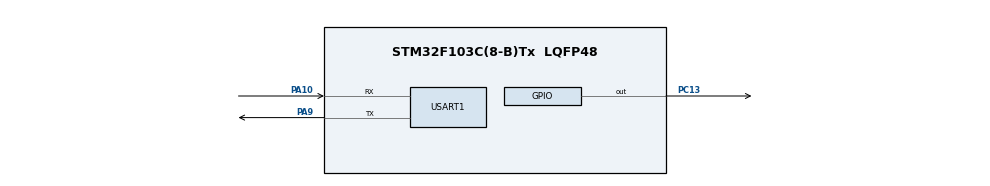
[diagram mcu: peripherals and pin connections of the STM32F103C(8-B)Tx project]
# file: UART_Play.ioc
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Mcu.Family=STM32F1
Mcu.Name=STM32F103C(8-B)Tx
Mcu.Package=LQFP48
NVIC.PriorityGroup=NVIC_PRIORITYGROUP_4
NVIC.USART1_IRQn=true\:0\:0\:false\:false\:true\:true\:true\:true
PA10.Mode=Asynchronous
PA10.Signal=USART1_RX
PA9.Mode=Asynchronous
PA9.Signal=USART1_TX
PC13-TAMPER-RTC.Signal=GPIO_Output
ProjectManager.HeapSize=0x200
ProjectManager.StackSize=0x400
ProjectManager.TargetToolchain=STM32CubeIDE
RCC.APB1Freq_Value=8000000
RCC.APB2Freq_Value=8000000
USART1.VirtualMode=VM_ASYNC
VP_SYS_VS_ND.Mode=No_Debug
board=custom

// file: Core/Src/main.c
/* USER CODE BEGIN Header */
/**
  ******************************************************************************
  * @file           : main.c
  * @brief          : Main program body
  ******************************************************************************
  * @attention
  *
  * Copyright (c) 2025 STMicroelectronics.
  * All rights reserved.
  *
  * This software is licensed under terms that can be found in the LICENSE file
  * in the root directory of this software component.
  * If no LICENSE file comes with this software, it is provided AS-IS.
  *
  ******************************************************************************
  */
/* USER CODE END Header */
#include "main.h"
#include <stdbool.h>

UART_HandleTypeDef huart1;

/* USER CODE BEGIN PV */
#define SIZE_DATA 16

uint8_t tx_data[] = "Got data\n\r";
uint8_t rx_data[SIZE_DATA];
uint8_t command_set[] = "PIN_SET";
uint8_t command_reset[] = "PIN_RESET";
bool is_set;
/* USER CODE END PV */

void SystemClock_Config(void);
static void MX_GPIO_Init(void);
static void MX_USART1_UART_Init(void);

int main(void)
{

  /* MCU Configuration--------------------------------------------------------*/

  /* Reset of all peripherals, Initializes the Flash interface and the Systick. */
  HAL_Init();

  /* Configure the system clock */
  SystemClock_Config();

  /* Initialize all configured peripherals */
  MX_GPIO_Init();
  MX_USART1_UART_Init();
  /* USER CODE BEGIN 2 */
  HAL_UART_Receive_IT(&huart1, rx_data, SIZE_DATA);
  is_set = false;

  /* USER CODE END 2 */

  /* Infinite loop */
  while (1)
  {

    /* USER CODE BEGIN 3 */
	  HAL_GPIO_WritePin(GPIOC, GPIO_PIN_13, is_set ? GPIO_PIN_RESET : GPIO_PIN_SET);
	  HAL_Delay(200);
  }
  /* USER CODE END 3 */
}

void SystemClock_Config(void)
{
  RCC_OscInitTypeDef RCC_OscInitStruct = {0};
  RCC_ClkInitTypeDef RCC_ClkInitStruct = {0};

  /** Initializes the RCC Oscillators according to the specified parameters
  * in the RCC_OscInitTypeDef structure.
  */
  RCC_OscInitStruct.OscillatorType = RCC_OSCILLATORTYPE_HSI;
  RCC_OscInitStruct.HSIState = RCC_HSI_ON;
  RCC_OscInitStruct.HSICalibrationValue = RCC_HSICALIBRATION_DEFAULT;
  RCC_OscInitStruct.PLL.PLLState = RCC_PLL_NONE;
  if (HAL_RCC_OscConfig(&RCC_OscInitStruct) != HAL_OK)
  {
    Error_Handler();
  }

  /** Initializes the CPU, AHB and APB buses clocks
  */
  RCC_ClkInitStruct.ClockType = RCC_CLOCKTYPE_HCLK|RCC_CLOCKTYPE_SYSCLK
                              |RCC_CLOCKTYPE_PCLK1|RCC_CLOCKTYPE_PCLK2;
  RCC_ClkInitStruct.SYSCLKSource = RCC_SYSCLKSOURCE_HSI;
  RCC_ClkInitStruct.AHBCLKDivider = RCC_SYSCLK_DIV1;
  RCC_ClkInitStruct.APB1CLKDivider = RCC_HCLK_DIV1;
  RCC_ClkInitStruct.APB2CLKDivider = RCC_HCLK_DIV1;

  if (HAL_RCC_ClockConfig(&RCC_ClkInitStruct, FLASH_LATENCY_0) != HAL_OK)
  {
    Error_Handler();
  }
}

static void MX_USART1_UART_Init(void)
{

  huart1.Instance = USART1;
  huart1.Init.BaudRate = 115200;
  huart1.Init.WordLength = UART_WORDLENGTH_8B;
  huart1.Init.StopBits = UART_STOPBITS_1;
  huart1.Init.Parity = UART_PARITY_NONE;
  huart1.Init.Mode = UART_MODE_TX_RX;
  huart1.Init.HwFlowCtl = UART_HWCONTROL_NONE;
  huart1.Init.OverSampling = UART_OVERSAMPLING_16;
  if (HAL_UART_Init(&huart1) != HAL_OK)
  {
    Error_Handler();
  }

}

static void MX_GPIO_Init(void)
{
  GPIO_InitTypeDef GPIO_InitStruct = {0};

  /* GPIO Ports Clock Enable */
  __HAL_RCC_GPIOC_CLK_ENABLE();
  __HAL_RCC_GPIOA_CLK_ENABLE();

  /*Configure GPIO pin Output Level */
  HAL_GPIO_WritePin(GPIOC, GPIO_PIN_13, GPIO_PIN_SET);

  /*Configure GPIO pin : PC13 */
  GPIO_InitStruct.Pin = GPIO_PIN_13;
  GPIO_InitStruct.Mode = GPIO_MODE_OUTPUT_PP;
  GPIO_InitStruct.Pull = GPIO_NOPULL;
  GPIO_InitStruct.Speed = GPIO_SPEED_FREQ_LOW;
  HAL_GPIO_Init(GPIOC, &GPIO_InitStruct);

  /*Configure GPIO pin : PB6 UART_TX*/
  GPIO_InitStruct.Pin = GPIO_PIN_6;
  GPIO_InitStruct.Mode = GPIO_MODE_AF_PP;
  GPIO_InitStruct.Speed = GPIO_SPEED_FREQ_HIGH;
  HAL_GPIO_Init(GPIOA, &GPIO_InitStruct);

  /*Configure GPIO pin : PB6 UART_RX*/
  GPIO_InitStruct.Pin = GPIO_PIN_7;
  GPIO_InitStruct.Mode = GPIO_MODE_INPUT;
  GPIO_InitStruct.Pull = GPIO_NOPULL;
  HAL_GPIO_Init(GPIOA, &GPIO_InitStruct);

}

/* USER CODE BEGIN 4 */
void HAL_UART_RxCpltCallback(UART_HandleTypeDef *huart)
{
	HAL_UART_Transmit(&huart1, tx_data, 13, 100);
	for(int i = 0; i < SIZE_DATA; ++i)
		if(rx_data[i] == '\r' || i == SIZE_DATA - 1)
			rx_data[i] = '\0';

	if(!strcmp(command_set, rx_data)) {
		is_set = true;
	} else if(!strcmp(command_reset, rx_data)) {
		is_set = false;
	} else {
		  HAL_GPIO_WritePin(GPIOC, GPIO_PIN_13, is_set ? GPIO_PIN_SET : GPIO_PIN_RESET);
		  HAL_Delay(100);
		  HAL_GPIO_WritePin(GPIOC, GPIO_PIN_13, is_set ? GPIO_PIN_RESET : GPIO_PIN_SET);
		  HAL_Delay(100);
		  HAL_GPIO_WritePin(GPIOC, GPIO_PIN_13, is_set ? GPIO_PIN_SET : GPIO_PIN_RESET);
		  HAL_Delay(100);
	}

	memset(rx_data, '0', SIZE_DATA);
	HAL_UART_Receive_IT(&huart1, rx_data, SIZE_DATA);
}
/* USER CODE END 4 */

void Error_Handler(void)
{
  __disable_irq();
  while (1)
  {
  }
}
